VERSION 5.7 ;
  NOWIREEXTENSIONATPIN ON ;
  DIVIDERCHAR "/" ;
  BUSBITCHARS "[]" ;
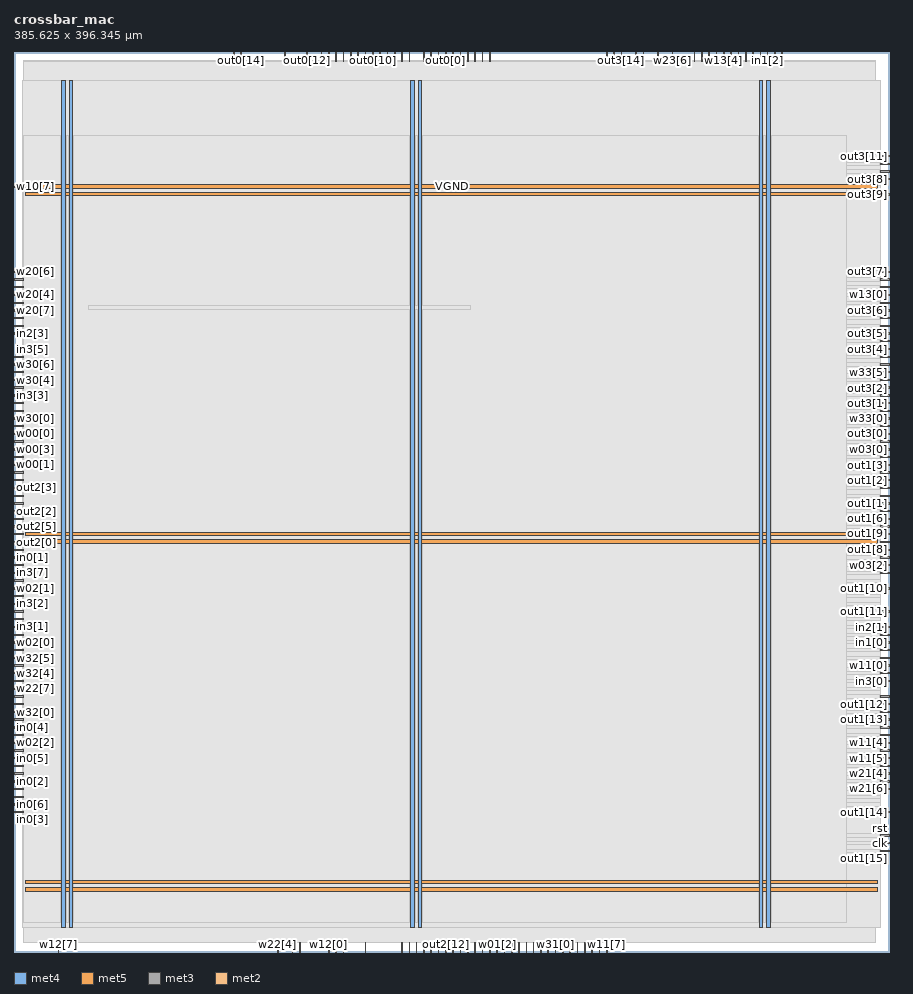
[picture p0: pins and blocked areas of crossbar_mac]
MACRO crossbar_mac
  CLASS BLOCK ;
  FOREIGN crossbar_mac ;
  ORIGIN 0.000 0.000 ;
  SIZE 385.625 BY 396.345 ;
  PIN VGND
    DIRECTION INOUT ;
    USE GROUND ;
    PORT
      LAYER met4 ;
        RECT 24.340 10.640 25.940 383.760 ;
    END
    PORT
      LAYER met4 ;
        RECT 177.940 10.640 179.540 383.760 ;
    END
    PORT
      LAYER met4 ;
        RECT 331.540 10.640 333.140 383.760 ;
    END
    PORT
      LAYER met5 ;
        RECT 5.280 30.030 380.200 31.630 ;
    END
    PORT
      LAYER met5 ;
        RECT 5.280 183.210 380.200 184.810 ;
    END
    PORT
      LAYER met5 ;
        RECT 5.280 336.390 380.200 337.990 ;
    END
  END VGND
  PIN VPWR
    DIRECTION INOUT ;
    USE POWER ;
    PORT
      LAYER met4 ;
        RECT 21.040 10.640 22.640 383.760 ;
    END
    PORT
      LAYER met4 ;
        RECT 174.640 10.640 176.240 383.760 ;
    END
    PORT
      LAYER met4 ;
        RECT 328.240 10.640 329.840 383.760 ;
    END
    PORT
      LAYER met5 ;
        RECT 5.280 26.730 380.200 28.330 ;
    END
    PORT
      LAYER met5 ;
        RECT 5.280 179.910 380.200 181.510 ;
    END
    PORT
      LAYER met5 ;
        RECT 5.280 333.090 380.200 334.690 ;
    END
  END VPWR
  PIN clk
    DIRECTION INPUT ;
    USE SIGNAL ;
    ANTENNAGATEAREA 0.852000 ;
    PORT
      LAYER met3 ;
        RECT 381.625 47.640 385.625 48.240 ;
    END
  END clk
  PIN in0[0]
    DIRECTION INPUT ;
    USE SIGNAL ;
    ANTENNAGATEAREA 0.213000 ;
    PORT
      LAYER met3 ;
        RECT 0.000 122.440 4.000 123.040 ;
    END
  END in0[0]
  PIN in0[1]
    DIRECTION INPUT ;
    USE SIGNAL ;
    ANTENNAGATEAREA 0.196500 ;
    PORT
      LAYER met3 ;
        RECT 0.000 173.440 4.000 174.040 ;
    END
  END in0[1]
  PIN in0[2]
    DIRECTION INPUT ;
    USE SIGNAL ;
    ANTENNAGATEAREA 0.495000 ;
    PORT
      LAYER met3 ;
        RECT 0.000 74.840 4.000 75.440 ;
    END
  END in0[2]
  PIN in0[3]
    DIRECTION INPUT ;
    USE SIGNAL ;
    ANTENNAGATEAREA 0.990000 ;
    PORT
      LAYER met3 ;
        RECT 0.000 61.240 4.000 61.840 ;
    END
  END in0[3]
  PIN in0[4]
    DIRECTION INPUT ;
    USE SIGNAL ;
    ANTENNAGATEAREA 0.990000 ;
    PORT
      LAYER met3 ;
        RECT 0.000 98.640 4.000 99.240 ;
    END
  END in0[4]
  PIN in0[5]
    DIRECTION INPUT ;
    USE SIGNAL ;
    ANTENNAGATEAREA 0.196500 ;
    PORT
      LAYER met3 ;
        RECT 0.000 85.040 4.000 85.640 ;
    END
  END in0[5]
  PIN in0[6]
    DIRECTION INPUT ;
    USE SIGNAL ;
    ANTENNAGATEAREA 0.159000 ;
    PORT
      LAYER met3 ;
        RECT 0.000 64.640 4.000 65.240 ;
    END
  END in0[6]
  PIN in0[7]
    DIRECTION INPUT ;
    USE SIGNAL ;
    ANTENNAGATEAREA 0.247500 ;
    PORT
      LAYER met3 ;
        RECT 0.000 88.440 4.000 89.040 ;
    END
  END in0[7]
  PIN in1[0]
    DIRECTION INPUT ;
    USE SIGNAL ;
    ANTENNAGATEAREA 0.213000 ;
    PORT
      LAYER met3 ;
        RECT 381.625 136.040 385.625 136.640 ;
    END
  END in1[0]
  PIN in1[1]
    DIRECTION INPUT ;
    USE SIGNAL ;
    ANTENNAGATEAREA 0.213000 ;
    PORT
      LAYER met2 ;
        RECT 338.190 392.345 338.470 396.345 ;
    END
  END in1[1]
  PIN in1[2]
    DIRECTION INPUT ;
    USE SIGNAL ;
    ANTENNAGATEAREA 0.196500 ;
    PORT
      LAYER met2 ;
        RECT 331.750 392.345 332.030 396.345 ;
    END
  END in1[2]
  PIN in1[3]
    DIRECTION INPUT ;
    USE SIGNAL ;
    ANTENNAGATEAREA 0.196500 ;
    PORT
      LAYER met2 ;
        RECT 334.970 392.345 335.250 396.345 ;
    END
  END in1[3]
  PIN in1[4]
    DIRECTION INPUT ;
    USE SIGNAL ;
    ANTENNAGATEAREA 0.196500 ;
    PORT
      LAYER met2 ;
        RECT 328.530 392.345 328.810 396.345 ;
    END
  END in1[4]
  PIN in1[5]
    DIRECTION INPUT ;
    USE SIGNAL ;
    ANTENNAGATEAREA 0.213000 ;
    PORT
      LAYER met2 ;
        RECT 325.310 392.345 325.590 396.345 ;
    END
  END in1[5]
  PIN in1[6]
    DIRECTION INPUT ;
    USE SIGNAL ;
    ANTENNAGATEAREA 0.213000 ;
    PORT
      LAYER met2 ;
        RECT 322.090 392.345 322.370 396.345 ;
    END
  END in1[6]
  PIN in1[7]
    DIRECTION INPUT ;
    USE SIGNAL ;
    ANTENNAGATEAREA 0.196500 ;
    PORT
      LAYER met2 ;
        RECT 318.870 392.345 319.150 396.345 ;
    END
  END in1[7]
  PIN in2[0]
    DIRECTION INPUT ;
    USE SIGNAL ;
    ANTENNAGATEAREA 0.213000 ;
    PORT
      LAYER met3 ;
        RECT 381.625 122.440 385.625 123.040 ;
    END
  END in2[0]
  PIN in2[1]
    DIRECTION INPUT ;
    USE SIGNAL ;
    ANTENNAGATEAREA 0.213000 ;
    PORT
      LAYER met3 ;
        RECT 381.625 139.440 385.625 140.040 ;
    END
  END in2[1]
  PIN in2[2]
    DIRECTION INPUT ;
    USE SIGNAL ;
    ANTENNAGATEAREA 0.196500 ;
    PORT
      LAYER met3 ;
        RECT 381.625 112.240 385.625 112.840 ;
    END
  END in2[2]
  PIN in2[3]
    DIRECTION INPUT ;
    USE SIGNAL ;
    ANTENNAGATEAREA 0.196500 ;
    PORT
      LAYER met3 ;
        RECT 0.000 272.040 4.000 272.640 ;
    END
  END in2[3]
  PIN in2[4]
    DIRECTION INPUT ;
    USE SIGNAL ;
    ANTENNAGATEAREA 0.213000 ;
    PORT
      LAYER met3 ;
        RECT 0.000 292.440 4.000 293.040 ;
    END
  END in2[4]
  PIN in2[5]
    DIRECTION INPUT ;
    USE SIGNAL ;
    ANTENNAGATEAREA 0.213000 ;
    PORT
      LAYER met3 ;
        RECT 0.000 278.840 4.000 279.440 ;
    END
  END in2[5]
  PIN in2[6]
    DIRECTION INPUT ;
    USE SIGNAL ;
    ANTENNAGATEAREA 0.159000 ;
    PORT
      LAYER met3 ;
        RECT 0.000 275.440 4.000 276.040 ;
    END
  END in2[6]
  PIN in2[7]
    DIRECTION INPUT ;
    USE SIGNAL ;
    ANTENNAGATEAREA 0.196500 ;
    PORT
      LAYER met3 ;
        RECT 0.000 285.640 4.000 286.240 ;
    END
  END in2[7]
  PIN in3[0]
    DIRECTION INPUT ;
    USE SIGNAL ;
    ANTENNAGATEAREA 0.159000 ;
    PORT
      LAYER met3 ;
        RECT 381.625 119.040 385.625 119.640 ;
    END
  END in3[0]
  PIN in3[1]
    DIRECTION INPUT ;
    USE SIGNAL ;
    ANTENNAGATEAREA 0.213000 ;
    PORT
      LAYER met3 ;
        RECT 0.000 142.840 4.000 143.440 ;
    END
  END in3[1]
  PIN in3[2]
    DIRECTION INPUT ;
    USE SIGNAL ;
    ANTENNAGATEAREA 0.159000 ;
    PORT
      LAYER met3 ;
        RECT 0.000 153.040 4.000 153.640 ;
    END
  END in3[2]
  PIN in3[3]
    DIRECTION INPUT ;
    USE SIGNAL ;
    ANTENNAGATEAREA 0.213000 ;
    PORT
      LAYER met3 ;
        RECT 0.000 244.840 4.000 245.440 ;
    END
  END in3[3]
  PIN in3[4]
    DIRECTION INPUT ;
    USE SIGNAL ;
    ANTENNAGATEAREA 0.196500 ;
    PORT
      LAYER met3 ;
        RECT 0.000 112.240 4.000 112.840 ;
    END
  END in3[4]
  PIN in3[5]
    DIRECTION INPUT ;
    USE SIGNAL ;
    ANTENNAGATEAREA 0.196500 ;
    PORT
      LAYER met3 ;
        RECT 0.000 261.840 4.000 262.440 ;
    END
  END in3[5]
  PIN in3[6]
    DIRECTION INPUT ;
    USE SIGNAL ;
    ANTENNAGATEAREA 0.213000 ;
    PORT
      LAYER met3 ;
        RECT 0.000 105.440 4.000 106.040 ;
    END
  END in3[6]
  PIN in3[7]
    DIRECTION INPUT ;
    USE SIGNAL ;
    ANTENNAGATEAREA 0.213000 ;
    PORT
      LAYER met3 ;
        RECT 0.000 170.040 4.000 170.640 ;
    END
  END in3[7]
  PIN out0[0]
    DIRECTION OUTPUT ;
    USE SIGNAL ;
    ANTENNADIFFAREA 0.445500 ;
    PORT
      LAYER met2 ;
        RECT 190.070 392.345 190.350 396.345 ;
    END
  END out0[0]
  PIN out0[10]
    DIRECTION OUTPUT ;
    USE SIGNAL ;
    ANTENNADIFFAREA 0.445500 ;
    PORT
      LAYER met2 ;
        RECT 157.870 392.345 158.150 396.345 ;
    END
  END out0[10]
  PIN out0[11]
    DIRECTION OUTPUT ;
    USE SIGNAL ;
    ANTENNADIFFAREA 0.445500 ;
    PORT
      LAYER met2 ;
        RECT 151.430 392.345 151.710 396.345 ;
    END
  END out0[11]
  PIN out0[12]
    DIRECTION OUTPUT ;
    USE SIGNAL ;
    ANTENNADIFFAREA 0.445500 ;
    PORT
      LAYER met2 ;
        RECT 128.890 392.345 129.170 396.345 ;
    END
  END out0[12]
  PIN out0[13]
    DIRECTION OUTPUT ;
    USE SIGNAL ;
    ANTENNADIFFAREA 0.445500 ;
    PORT
      LAYER met2 ;
        RECT 119.230 392.345 119.510 396.345 ;
    END
  END out0[13]
  PIN out0[14]
    DIRECTION OUTPUT ;
    USE SIGNAL ;
    ANTENNADIFFAREA 0.445500 ;
    PORT
      LAYER met2 ;
        RECT 99.910 392.345 100.190 396.345 ;
    END
  END out0[14]
  PIN out0[15]
    DIRECTION OUTPUT ;
    USE SIGNAL ;
    ANTENNADIFFAREA 0.445500 ;
    PORT
      LAYER met2 ;
        RECT 96.690 392.345 96.970 396.345 ;
    END
  END out0[15]
  PIN out0[1]
    DIRECTION OUTPUT ;
    USE SIGNAL ;
    ANTENNADIFFAREA 0.445500 ;
    PORT
      LAYER met2 ;
        RECT 196.510 392.345 196.790 396.345 ;
    END
  END out0[1]
  PIN out0[2]
    DIRECTION OUTPUT ;
    USE SIGNAL ;
    ANTENNADIFFAREA 0.445500 ;
    PORT
      LAYER met2 ;
        RECT 209.390 392.345 209.670 396.345 ;
    END
  END out0[2]
  PIN out0[3]
    DIRECTION OUTPUT ;
    USE SIGNAL ;
    ANTENNADIFFAREA 0.445500 ;
    PORT
      LAYER met2 ;
        RECT 206.170 392.345 206.450 396.345 ;
    END
  END out0[3]
  PIN out0[4]
    DIRECTION OUTPUT ;
    USE SIGNAL ;
    ANTENNADIFFAREA 0.445500 ;
    PORT
      LAYER met2 ;
        RECT 199.730 392.345 200.010 396.345 ;
    END
  END out0[4]
  PIN out0[5]
    DIRECTION OUTPUT ;
    USE SIGNAL ;
    ANTENNADIFFAREA 0.445500 ;
    PORT
      LAYER met2 ;
        RECT 202.950 392.345 203.230 396.345 ;
    END
  END out0[5]
  PIN out0[6]
    DIRECTION OUTPUT ;
    USE SIGNAL ;
    ANTENNADIFFAREA 0.445500 ;
    PORT
      LAYER met2 ;
        RECT 193.290 392.345 193.570 396.345 ;
    END
  END out0[6]
  PIN out0[7]
    DIRECTION OUTPUT ;
    USE SIGNAL ;
    ANTENNADIFFAREA 0.445500 ;
    PORT
      LAYER met2 ;
        RECT 186.850 392.345 187.130 396.345 ;
    END
  END out0[7]
  PIN out0[8]
    DIRECTION OUTPUT ;
    USE SIGNAL ;
    ANTENNADIFFAREA 0.445500 ;
    PORT
      LAYER met2 ;
        RECT 183.630 392.345 183.910 396.345 ;
    END
  END out0[8]
  PIN out0[9]
    DIRECTION OUTPUT ;
    USE SIGNAL ;
    ANTENNADIFFAREA 0.445500 ;
    PORT
      LAYER met2 ;
        RECT 180.410 392.345 180.690 396.345 ;
    END
  END out0[9]
  PIN out1[0]
    DIRECTION OUTPUT ;
    USE SIGNAL ;
    ANTENNADIFFAREA 0.445500 ;
    PORT
      LAYER met3 ;
        RECT 381.625 166.640 385.625 167.240 ;
    END
  END out1[0]
  PIN out1[10]
    DIRECTION OUTPUT ;
    USE SIGNAL ;
    ANTENNADIFFAREA 0.445500 ;
    PORT
      LAYER met3 ;
        RECT 381.625 159.840 385.625 160.440 ;
    END
  END out1[10]
  PIN out1[11]
    DIRECTION OUTPUT ;
    USE SIGNAL ;
    ANTENNADIFFAREA 0.445500 ;
    PORT
      LAYER met3 ;
        RECT 381.625 149.640 385.625 150.240 ;
    END
  END out1[11]
  PIN out1[12]
    DIRECTION OUTPUT ;
    USE SIGNAL ;
    ANTENNADIFFAREA 0.445500 ;
    PORT
      LAYER met3 ;
        RECT 381.625 108.840 385.625 109.440 ;
    END
  END out1[12]
  PIN out1[13]
    DIRECTION OUTPUT ;
    USE SIGNAL ;
    ANTENNADIFFAREA 0.445500 ;
    PORT
      LAYER met3 ;
        RECT 381.625 102.040 385.625 102.640 ;
    END
  END out1[13]
  PIN out1[14]
    DIRECTION OUTPUT ;
    USE SIGNAL ;
    ANTENNADIFFAREA 0.445500 ;
    PORT
      LAYER met3 ;
        RECT 381.625 61.240 385.625 61.840 ;
    END
  END out1[14]
  PIN out1[15]
    DIRECTION OUTPUT ;
    USE SIGNAL ;
    ANTENNADIFFAREA 0.445500 ;
    PORT
      LAYER met3 ;
        RECT 381.625 44.240 385.625 44.840 ;
    END
  END out1[15]
  PIN out1[1]
    DIRECTION OUTPUT ;
    USE SIGNAL ;
    ANTENNADIFFAREA 0.445500 ;
    PORT
      LAYER met3 ;
        RECT 381.625 197.240 385.625 197.840 ;
    END
  END out1[1]
  PIN out1[2]
    DIRECTION OUTPUT ;
    USE SIGNAL ;
    ANTENNADIFFAREA 0.445500 ;
    PORT
      LAYER met3 ;
        RECT 381.625 207.440 385.625 208.040 ;
    END
  END out1[2]
  PIN out1[3]
    DIRECTION OUTPUT ;
    USE SIGNAL ;
    ANTENNADIFFAREA 0.445500 ;
    PORT
      LAYER met3 ;
        RECT 381.625 210.840 385.625 211.440 ;
    END
  END out1[3]
  PIN out1[4]
    DIRECTION OUTPUT ;
    USE SIGNAL ;
    ANTENNADIFFAREA 0.445500 ;
    PORT
      LAYER met3 ;
        RECT 381.625 204.040 385.625 204.640 ;
    END
  END out1[4]
  PIN out1[5]
    DIRECTION OUTPUT ;
    USE SIGNAL ;
    ANTENNADIFFAREA 0.445500 ;
    PORT
      LAYER met3 ;
        RECT 381.625 200.640 385.625 201.240 ;
    END
  END out1[5]
  PIN out1[6]
    DIRECTION OUTPUT ;
    USE SIGNAL ;
    ANTENNADIFFAREA 0.445500 ;
    PORT
      LAYER met3 ;
        RECT 381.625 193.840 385.625 194.440 ;
    END
  END out1[6]
  PIN out1[7]
    DIRECTION OUTPUT ;
    USE SIGNAL ;
    ANTENNADIFFAREA 0.445500 ;
    PORT
      LAYER met3 ;
        RECT 381.625 190.440 385.625 191.040 ;
    END
  END out1[7]
  PIN out1[8]
    DIRECTION OUTPUT ;
    USE SIGNAL ;
    ANTENNADIFFAREA 0.445500 ;
    PORT
      LAYER met3 ;
        RECT 381.625 176.840 385.625 177.440 ;
    END
  END out1[8]
  PIN out1[9]
    DIRECTION OUTPUT ;
    USE SIGNAL ;
    ANTENNADIFFAREA 0.445500 ;
    PORT
      LAYER met3 ;
        RECT 381.625 187.040 385.625 187.640 ;
    END
  END out1[9]
  PIN out2[0]
    DIRECTION OUTPUT ;
    USE SIGNAL ;
    ANTENNADIFFAREA 0.445500 ;
    PORT
      LAYER met3 ;
        RECT 0.000 176.840 4.000 177.440 ;
    END
  END out2[0]
  PIN out2[10]
    DIRECTION OUTPUT ;
    USE SIGNAL ;
    ANTENNADIFFAREA 0.445500 ;
    PORT
      LAYER met2 ;
        RECT 206.170 0.000 206.450 4.000 ;
    END
  END out2[10]
  PIN out2[11]
    DIRECTION OUTPUT ;
    USE SIGNAL ;
    ANTENNADIFFAREA 0.445500 ;
    PORT
      LAYER met2 ;
        RECT 222.270 0.000 222.550 4.000 ;
    END
  END out2[11]
  PIN out2[12]
    DIRECTION OUTPUT ;
    USE SIGNAL ;
    ANTENNADIFFAREA 0.445500 ;
    PORT
      LAYER met2 ;
        RECT 190.070 0.000 190.350 4.000 ;
    END
  END out2[12]
  PIN out2[13]
    DIRECTION OUTPUT ;
    USE SIGNAL ;
    ANTENNADIFFAREA 0.445500 ;
    PORT
      LAYER met2 ;
        RECT 186.850 0.000 187.130 4.000 ;
    END
  END out2[13]
  PIN out2[14]
    DIRECTION OUTPUT ;
    USE SIGNAL ;
    ANTENNADIFFAREA 0.445500 ;
    PORT
      LAYER met2 ;
        RECT 180.410 0.000 180.690 4.000 ;
    END
  END out2[14]
  PIN out2[15]
    DIRECTION OUTPUT ;
    USE SIGNAL ;
    ANTENNADIFFAREA 0.445500 ;
    PORT
      LAYER met2 ;
        RECT 177.190 0.000 177.470 4.000 ;
    END
  END out2[15]
  PIN out2[1]
    DIRECTION OUTPUT ;
    USE SIGNAL ;
    ANTENNADIFFAREA 0.445500 ;
    PORT
      LAYER met3 ;
        RECT 0.000 180.240 4.000 180.840 ;
    END
  END out2[1]
  PIN out2[2]
    DIRECTION OUTPUT ;
    USE SIGNAL ;
    ANTENNADIFFAREA 0.445500 ;
    PORT
      LAYER met3 ;
        RECT 0.000 193.840 4.000 194.440 ;
    END
  END out2[2]
  PIN out2[3]
    DIRECTION OUTPUT ;
    USE SIGNAL ;
    ANTENNADIFFAREA 0.445500 ;
    PORT
      LAYER met3 ;
        RECT 0.000 204.040 4.000 204.640 ;
    END
  END out2[3]
  PIN out2[4]
    DIRECTION OUTPUT ;
    USE SIGNAL ;
    ANTENNADIFFAREA 0.445500 ;
    PORT
      LAYER met3 ;
        RECT 0.000 200.640 4.000 201.240 ;
    END
  END out2[4]
  PIN out2[5]
    DIRECTION OUTPUT ;
    USE SIGNAL ;
    ANTENNADIFFAREA 0.445500 ;
    PORT
      LAYER met3 ;
        RECT 0.000 190.440 4.000 191.040 ;
    END
  END out2[5]
  PIN out2[6]
    DIRECTION OUTPUT ;
    USE SIGNAL ;
    ANTENNADIFFAREA 0.445500 ;
    PORT
      LAYER met3 ;
        RECT 0.000 197.240 4.000 197.840 ;
    END
  END out2[6]
  PIN out2[7]
    DIRECTION OUTPUT ;
    USE SIGNAL ;
    ANTENNADIFFAREA 0.445500 ;
    PORT
      LAYER met3 ;
        RECT 0.000 183.640 4.000 184.240 ;
    END
  END out2[7]
  PIN out2[8]
    DIRECTION OUTPUT ;
    USE SIGNAL ;
    ANTENNADIFFAREA 0.445500 ;
    PORT
      LAYER met2 ;
        RECT 199.730 0.000 200.010 4.000 ;
    END
  END out2[8]
  PIN out2[9]
    DIRECTION OUTPUT ;
    USE SIGNAL ;
    ANTENNADIFFAREA 0.445500 ;
    PORT
      LAYER met2 ;
        RECT 202.950 0.000 203.230 4.000 ;
    END
  END out2[9]
  PIN out3[0]
    DIRECTION OUTPUT ;
    USE SIGNAL ;
    ANTENNADIFFAREA 0.445500 ;
    PORT
      LAYER met3 ;
        RECT 381.625 227.840 385.625 228.440 ;
    END
  END out3[0]
  PIN out3[10]
    DIRECTION OUTPUT ;
    USE SIGNAL ;
    ANTENNADIFFAREA 0.445500 ;
    PORT
      LAYER met3 ;
        RECT 381.625 343.440 385.625 344.040 ;
    END
  END out3[10]
  PIN out3[11]
    DIRECTION OUTPUT ;
    USE SIGNAL ;
    ANTENNADIFFAREA 0.445500 ;
    PORT
      LAYER met3 ;
        RECT 381.625 350.240 385.625 350.840 ;
    END
  END out3[11]
  PIN out3[12]
    DIRECTION OUTPUT ;
    USE SIGNAL ;
    ANTENNADIFFAREA 0.445500 ;
    PORT
      LAYER met3 ;
        RECT 381.625 346.840 385.625 347.440 ;
    END
  END out3[12]
  PIN out3[13]
    DIRECTION OUTPUT ;
    USE SIGNAL ;
    ANTENNADIFFAREA 0.445500 ;
    PORT
      LAYER met2 ;
        RECT 283.450 392.345 283.730 396.345 ;
    END
  END out3[13]
  PIN out3[14]
    DIRECTION OUTPUT ;
    USE SIGNAL ;
    ANTENNADIFFAREA 0.445500 ;
    PORT
      LAYER met2 ;
        RECT 267.350 392.345 267.630 396.345 ;
    END
  END out3[14]
  PIN out3[15]
    DIRECTION OUTPUT ;
    USE SIGNAL ;
    ANTENNADIFFAREA 0.445500 ;
    PORT
      LAYER met2 ;
        RECT 264.130 392.345 264.410 396.345 ;
    END
  END out3[15]
  PIN out3[1]
    DIRECTION OUTPUT ;
    USE SIGNAL ;
    ANTENNADIFFAREA 0.445500 ;
    PORT
      LAYER met3 ;
        RECT 381.625 241.440 385.625 242.040 ;
    END
  END out3[1]
  PIN out3[2]
    DIRECTION OUTPUT ;
    USE SIGNAL ;
    ANTENNADIFFAREA 0.445500 ;
    PORT
      LAYER met3 ;
        RECT 381.625 244.840 385.625 245.440 ;
    END
  END out3[2]
  PIN out3[3]
    DIRECTION OUTPUT ;
    USE SIGNAL ;
    ANTENNADIFFAREA 0.445500 ;
    PORT
      LAYER met3 ;
        RECT 381.625 251.640 385.625 252.240 ;
    END
  END out3[3]
  PIN out3[4]
    DIRECTION OUTPUT ;
    USE SIGNAL ;
    ANTENNADIFFAREA 0.445500 ;
    PORT
      LAYER met3 ;
        RECT 381.625 265.240 385.625 265.840 ;
    END
  END out3[4]
  PIN out3[5]
    DIRECTION OUTPUT ;
    USE SIGNAL ;
    ANTENNADIFFAREA 0.445500 ;
    PORT
      LAYER met3 ;
        RECT 381.625 272.040 385.625 272.640 ;
    END
  END out3[5]
  PIN out3[6]
    DIRECTION OUTPUT ;
    USE SIGNAL ;
    ANTENNADIFFAREA 0.445500 ;
    PORT
      LAYER met3 ;
        RECT 381.625 282.240 385.625 282.840 ;
    END
  END out3[6]
  PIN out3[7]
    DIRECTION OUTPUT ;
    USE SIGNAL ;
    ANTENNADIFFAREA 0.445500 ;
    PORT
      LAYER met3 ;
        RECT 381.625 299.240 385.625 299.840 ;
    END
  END out3[7]
  PIN out3[8]
    DIRECTION OUTPUT ;
    USE SIGNAL ;
    ANTENNADIFFAREA 0.445500 ;
    PORT
      LAYER met3 ;
        RECT 381.625 340.040 385.625 340.640 ;
    END
  END out3[8]
  PIN out3[9]
    DIRECTION OUTPUT ;
    USE SIGNAL ;
    ANTENNADIFFAREA 0.445500 ;
    PORT
      LAYER met3 ;
        RECT 381.625 333.240 385.625 333.840 ;
    END
  END out3[9]
  PIN rst
    DIRECTION INPUT ;
    USE SIGNAL ;
    ANTENNAGATEAREA 0.247500 ;
    PORT
      LAYER met3 ;
        RECT 381.625 51.040 385.625 51.640 ;
    END
  END rst
  PIN w00[0]
    DIRECTION INPUT ;
    USE SIGNAL ;
    ANTENNAGATEAREA 0.159000 ;
    PORT
      LAYER met3 ;
        RECT 0.000 227.840 4.000 228.440 ;
    END
  END w00[0]
  PIN w00[1]
    DIRECTION INPUT ;
    USE SIGNAL ;
    ANTENNAGATEAREA 0.196500 ;
    PORT
      LAYER met3 ;
        RECT 0.000 214.240 4.000 214.840 ;
    END
  END w00[1]
  PIN w00[2]
    DIRECTION INPUT ;
    USE SIGNAL ;
    ANTENNAGATEAREA 0.213000 ;
    PORT
      LAYER met3 ;
        RECT 0.000 210.840 4.000 211.440 ;
    END
  END w00[2]
  PIN w00[3]
    DIRECTION INPUT ;
    USE SIGNAL ;
    ANTENNAGATEAREA 0.196500 ;
    PORT
      LAYER met3 ;
        RECT 0.000 221.040 4.000 221.640 ;
    END
  END w00[3]
  PIN w00[4]
    DIRECTION INPUT ;
    USE SIGNAL ;
    ANTENNAGATEAREA 0.196500 ;
    PORT
      LAYER met3 ;
        RECT 0.000 217.640 4.000 218.240 ;
    END
  END w00[4]
  PIN w00[5]
    DIRECTION INPUT ;
    USE SIGNAL ;
    ANTENNAGATEAREA 0.196500 ;
    PORT
      LAYER met3 ;
        RECT 0.000 207.440 4.000 208.040 ;
    END
  END w00[5]
  PIN w00[6]
    DIRECTION INPUT ;
    USE SIGNAL ;
    ANTENNAGATEAREA 0.213000 ;
    PORT
      LAYER met3 ;
        RECT 0.000 187.040 4.000 187.640 ;
    END
  END w00[6]
  PIN w00[7]
    DIRECTION INPUT ;
    USE SIGNAL ;
    ANTENNAGATEAREA 0.126000 ;
    PORT
      LAYER met3 ;
        RECT 0.000 224.440 4.000 225.040 ;
    END
  END w00[7]
  PIN w01[0]
    DIRECTION INPUT ;
    USE SIGNAL ;
    ANTENNAGATEAREA 0.213000 ;
    PORT
      LAYER met2 ;
        RECT 228.710 0.000 228.990 4.000 ;
    END
  END w01[0]
  PIN w01[1]
    DIRECTION INPUT ;
    USE SIGNAL ;
    ANTENNAGATEAREA 0.196500 ;
    PORT
      LAYER met2 ;
        RECT 225.490 0.000 225.770 4.000 ;
    END
  END w01[1]
  PIN w01[2]
    DIRECTION INPUT ;
    USE SIGNAL ;
    ANTENNAGATEAREA 0.213000 ;
    PORT
      LAYER met2 ;
        RECT 212.610 0.000 212.890 4.000 ;
    END
  END w01[2]
  PIN w01[3]
    DIRECTION INPUT ;
    USE SIGNAL ;
    ANTENNAGATEAREA 0.196500 ;
    PORT
      LAYER met2 ;
        RECT 219.050 0.000 219.330 4.000 ;
    END
  END w01[3]
  PIN w01[4]
    DIRECTION INPUT ;
    USE SIGNAL ;
    ANTENNAGATEAREA 0.196500 ;
    PORT
      LAYER met2 ;
        RECT 209.390 0.000 209.670 4.000 ;
    END
  END w01[4]
  PIN w01[5]
    DIRECTION INPUT ;
    USE SIGNAL ;
    ANTENNAGATEAREA 0.196500 ;
    PORT
      LAYER met2 ;
        RECT 196.510 0.000 196.790 4.000 ;
    END
  END w01[5]
  PIN w01[6]
    DIRECTION INPUT ;
    USE SIGNAL ;
    ANTENNAGATEAREA 0.213000 ;
    PORT
      LAYER met2 ;
        RECT 215.830 0.000 216.110 4.000 ;
    END
  END w01[6]
  PIN w01[7]
    DIRECTION INPUT ;
    USE SIGNAL ;
    ANTENNAGATEAREA 0.196500 ;
    PORT
      LAYER met2 ;
        RECT 193.290 0.000 193.570 4.000 ;
    END
  END w01[7]
  PIN w02[0]
    DIRECTION INPUT ;
    USE SIGNAL ;
    ANTENNAGATEAREA 0.196500 ;
    PORT
      LAYER met3 ;
        RECT 0.000 139.440 4.000 140.040 ;
    END
  END w02[0]
  PIN w02[1]
    DIRECTION INPUT ;
    USE SIGNAL ;
    ANTENNAGATEAREA 0.196500 ;
    PORT
      LAYER met3 ;
        RECT 0.000 159.840 4.000 160.440 ;
    END
  END w02[1]
  PIN w02[2]
    DIRECTION INPUT ;
    USE SIGNAL ;
    ANTENNAGATEAREA 0.159000 ;
    PORT
      LAYER met3 ;
        RECT 0.000 91.840 4.000 92.440 ;
    END
  END w02[2]
  PIN w02[3]
    DIRECTION INPUT ;
    USE SIGNAL ;
    ANTENNAGATEAREA 0.196500 ;
    PORT
      LAYER met3 ;
        RECT 0.000 68.040 4.000 68.640 ;
    END
  END w02[3]
  PIN w02[4]
    DIRECTION INPUT ;
    USE SIGNAL ;
    ANTENNAGATEAREA 0.196500 ;
    PORT
      LAYER met3 ;
        RECT 0.000 132.640 4.000 133.240 ;
    END
  END w02[4]
  PIN w02[5]
    DIRECTION INPUT ;
    USE SIGNAL ;
    ANTENNAGATEAREA 0.196500 ;
    PORT
      LAYER met3 ;
        RECT 0.000 78.240 4.000 78.840 ;
    END
  END w02[5]
  PIN w02[6]
    DIRECTION INPUT ;
    USE SIGNAL ;
    ANTENNAGATEAREA 0.126000 ;
    PORT
      LAYER met3 ;
        RECT 0.000 81.640 4.000 82.240 ;
    END
  END w02[6]
  PIN w02[7]
    DIRECTION INPUT ;
    USE SIGNAL ;
    ANTENNAGATEAREA 0.196500 ;
    PORT
      LAYER met3 ;
        RECT 0.000 95.240 4.000 95.840 ;
    END
  END w02[7]
  PIN w03[0]
    DIRECTION INPUT ;
    USE SIGNAL ;
    ANTENNAGATEAREA 0.196500 ;
    PORT
      LAYER met3 ;
        RECT 381.625 221.040 385.625 221.640 ;
    END
  END w03[0]
  PIN w03[1]
    DIRECTION INPUT ;
    USE SIGNAL ;
    ANTENNAGATEAREA 0.196500 ;
    PORT
      LAYER met3 ;
        RECT 381.625 214.240 385.625 214.840 ;
    END
  END w03[1]
  PIN w03[2]
    DIRECTION INPUT ;
    USE SIGNAL ;
    ANTENNAGATEAREA 0.213000 ;
    PORT
      LAYER met3 ;
        RECT 381.625 170.040 385.625 170.640 ;
    END
  END w03[2]
  PIN w03[3]
    DIRECTION INPUT ;
    USE SIGNAL ;
    ANTENNAGATEAREA 0.196500 ;
    PORT
      LAYER met3 ;
        RECT 381.625 217.640 385.625 218.240 ;
    END
  END w03[3]
  PIN w03[4]
    DIRECTION INPUT ;
    USE SIGNAL ;
    ANTENNAGATEAREA 0.196500 ;
    PORT
      LAYER met3 ;
        RECT 381.625 224.440 385.625 225.040 ;
    END
  END w03[4]
  PIN w03[5]
    DIRECTION INPUT ;
    USE SIGNAL ;
    ANTENNAGATEAREA 0.213000 ;
    PORT
      LAYER met3 ;
        RECT 381.625 173.440 385.625 174.040 ;
    END
  END w03[5]
  PIN w03[6]
    DIRECTION INPUT ;
    USE SIGNAL ;
    ANTENNAGATEAREA 0.213000 ;
    PORT
      LAYER met3 ;
        RECT 381.625 180.240 385.625 180.840 ;
    END
  END w03[6]
  PIN w03[7]
    DIRECTION INPUT ;
    USE SIGNAL ;
    ANTENNAGATEAREA 0.213000 ;
    PORT
      LAYER met3 ;
        RECT 381.625 183.640 385.625 184.240 ;
    END
  END w03[7]
  PIN w10[0]
    DIRECTION INPUT ;
    USE SIGNAL ;
    ANTENNAGATEAREA 0.196500 ;
    PORT
      LAYER met2 ;
        RECT 173.970 392.345 174.250 396.345 ;
    END
  END w10[0]
  PIN w10[1]
    DIRECTION INPUT ;
    USE SIGNAL ;
    ANTENNAGATEAREA 0.196500 ;
    PORT
      LAYER met2 ;
        RECT 170.750 392.345 171.030 396.345 ;
    END
  END w10[1]
  PIN w10[2]
    DIRECTION INPUT ;
    USE SIGNAL ;
    ANTENNAGATEAREA 0.196500 ;
    PORT
      LAYER met2 ;
        RECT 167.530 392.345 167.810 396.345 ;
    END
  END w10[2]
  PIN w10[3]
    DIRECTION INPUT ;
    USE SIGNAL ;
    ANTENNAGATEAREA 0.196500 ;
    PORT
      LAYER met2 ;
        RECT 164.310 392.345 164.590 396.345 ;
    END
  END w10[3]
  PIN w10[4]
    DIRECTION INPUT ;
    USE SIGNAL ;
    ANTENNAGATEAREA 0.196500 ;
    PORT
      LAYER met2 ;
        RECT 154.650 392.345 154.930 396.345 ;
    END
  END w10[4]
  PIN w10[5]
    DIRECTION INPUT ;
    USE SIGNAL ;
    ANTENNAGATEAREA 0.196500 ;
    PORT
      LAYER met2 ;
        RECT 148.210 392.345 148.490 396.345 ;
    END
  END w10[5]
  PIN w10[6]
    DIRECTION INPUT ;
    USE SIGNAL ;
    ANTENNAGATEAREA 0.196500 ;
    PORT
      LAYER met2 ;
        RECT 144.990 392.345 145.270 396.345 ;
    END
  END w10[6]
  PIN w10[7]
    DIRECTION INPUT ;
    USE SIGNAL ;
    ANTENNAGATEAREA 0.213000 ;
    PORT
      LAYER met3 ;
        RECT 0.000 336.640 4.000 337.240 ;
    END
  END w10[7]
  PIN w11[0]
    DIRECTION INPUT ;
    USE SIGNAL ;
    ANTENNAGATEAREA 0.196500 ;
    PORT
      LAYER met3 ;
        RECT 381.625 125.840 385.625 126.440 ;
    END
  END w11[0]
  PIN w11[1]
    DIRECTION INPUT ;
    USE SIGNAL ;
    ANTENNAGATEAREA 0.196500 ;
    PORT
      LAYER met3 ;
        RECT 381.625 129.240 385.625 129.840 ;
    END
  END w11[1]
  PIN w11[2]
    DIRECTION INPUT ;
    USE SIGNAL ;
    ANTENNAGATEAREA 0.126000 ;
    PORT
      LAYER met3 ;
        RECT 381.625 132.640 385.625 133.240 ;
    END
  END w11[2]
  PIN w11[3]
    DIRECTION INPUT ;
    USE SIGNAL ;
    ANTENNAGATEAREA 0.196500 ;
    PORT
      LAYER met3 ;
        RECT 381.625 88.440 385.625 89.040 ;
    END
  END w11[3]
  PIN w11[4]
    DIRECTION INPUT ;
    USE SIGNAL ;
    ANTENNAGATEAREA 0.196500 ;
    PORT
      LAYER met3 ;
        RECT 381.625 91.840 385.625 92.440 ;
    END
  END w11[4]
  PIN w11[5]
    DIRECTION INPUT ;
    USE SIGNAL ;
    ANTENNAGATEAREA 0.196500 ;
    PORT
      LAYER met3 ;
        RECT 381.625 85.040 385.625 85.640 ;
    END
  END w11[5]
  PIN w11[6]
    DIRECTION INPUT ;
    USE SIGNAL ;
    ANTENNAGATEAREA 0.196500 ;
    PORT
      LAYER met3 ;
        RECT 381.625 78.240 385.625 78.840 ;
    END
  END w11[6]
  PIN w11[7]
    DIRECTION INPUT ;
    USE SIGNAL ;
    ANTENNAGATEAREA 0.213000 ;
    PORT
      LAYER met2 ;
        RECT 260.910 0.000 261.190 4.000 ;
    END
  END w11[7]
  PIN w12[0]
    DIRECTION INPUT ;
    USE SIGNAL ;
    ANTENNAGATEAREA 0.196500 ;
    PORT
      LAYER met2 ;
        RECT 138.550 0.000 138.830 4.000 ;
    END
  END w12[0]
  PIN w12[1]
    DIRECTION INPUT ;
    USE SIGNAL ;
    ANTENNAGATEAREA 0.196500 ;
    PORT
      LAYER met2 ;
        RECT 141.770 0.000 142.050 4.000 ;
    END
  END w12[1]
  PIN w12[2]
    DIRECTION INPUT ;
    USE SIGNAL ;
    ANTENNAGATEAREA 0.159000 ;
    PORT
      LAYER met2 ;
        RECT 144.990 0.000 145.270 4.000 ;
    END
  END w12[2]
  PIN w12[3]
    DIRECTION INPUT ;
    USE SIGNAL ;
    ANTENNAGATEAREA 0.126000 ;
    PORT
      LAYER met2 ;
        RECT 170.750 0.000 171.030 4.000 ;
    END
  END w12[3]
  PIN w12[4]
    DIRECTION INPUT ;
    USE SIGNAL ;
    ANTENNAGATEAREA 0.126000 ;
    PORT
      LAYER met2 ;
        RECT 173.970 0.000 174.250 4.000 ;
    END
  END w12[4]
  PIN w12[5]
    DIRECTION INPUT ;
    USE SIGNAL ;
    ANTENNAGATEAREA 0.213000 ;
    PORT
      LAYER met2 ;
        RECT 183.630 0.000 183.910 4.000 ;
    END
  END w12[5]
  PIN w12[6]
    DIRECTION INPUT ;
    USE SIGNAL ;
    ANTENNAGATEAREA 0.196500 ;
    PORT
      LAYER met2 ;
        RECT 154.650 0.000 154.930 4.000 ;
    END
  END w12[6]
  PIN w12[7]
    DIRECTION INPUT ;
    USE SIGNAL ;
    ANTENNAGATEAREA 0.247500 ;
    PORT
      LAYER met2 ;
        RECT 19.410 0.000 19.690 4.000 ;
    END
  END w12[7]
  PIN w13[0]
    DIRECTION INPUT ;
    USE SIGNAL ;
    ANTENNAGATEAREA 0.196500 ;
    PORT
      LAYER met3 ;
        RECT 381.625 289.040 385.625 289.640 ;
    END
  END w13[0]
  PIN w13[1]
    DIRECTION INPUT ;
    USE SIGNAL ;
    ANTENNAGATEAREA 0.196500 ;
    PORT
      LAYER met3 ;
        RECT 381.625 292.440 385.625 293.040 ;
    END
  END w13[1]
  PIN w13[2]
    DIRECTION INPUT ;
    USE SIGNAL ;
    ANTENNAGATEAREA 0.196500 ;
    PORT
      LAYER met3 ;
        RECT 381.625 295.840 385.625 296.440 ;
    END
  END w13[2]
  PIN w13[3]
    DIRECTION INPUT ;
    USE SIGNAL ;
    ANTENNAGATEAREA 0.196500 ;
    PORT
      LAYER met2 ;
        RECT 315.650 392.345 315.930 396.345 ;
    END
  END w13[3]
  PIN w13[4]
    DIRECTION INPUT ;
    USE SIGNAL ;
    ANTENNAGATEAREA 0.196500 ;
    PORT
      LAYER met2 ;
        RECT 312.430 392.345 312.710 396.345 ;
    END
  END w13[4]
  PIN w13[5]
    DIRECTION INPUT ;
    USE SIGNAL ;
    ANTENNAGATEAREA 0.196500 ;
    PORT
      LAYER met2 ;
        RECT 309.210 392.345 309.490 396.345 ;
    END
  END w13[5]
  PIN w13[6]
    DIRECTION INPUT ;
    USE SIGNAL ;
    ANTENNAGATEAREA 0.196500 ;
    PORT
      LAYER met2 ;
        RECT 305.990 392.345 306.270 396.345 ;
    END
  END w13[6]
  PIN w13[7]
    DIRECTION INPUT ;
    USE SIGNAL ;
    ANTENNAGATEAREA 0.213000 ;
    PORT
      LAYER met2 ;
        RECT 277.010 392.345 277.290 396.345 ;
    END
  END w13[7]
  PIN w20[0]
    DIRECTION INPUT ;
    USE SIGNAL ;
    ANTENNAGATEAREA 0.213000 ;
    PORT
      LAYER met2 ;
        RECT 161.090 392.345 161.370 396.345 ;
    END
  END w20[0]
  PIN w20[1]
    DIRECTION INPUT ;
    USE SIGNAL ;
    ANTENNAGATEAREA 0.213000 ;
    PORT
      LAYER met2 ;
        RECT 141.770 392.345 142.050 396.345 ;
    END
  END w20[1]
  PIN w20[2]
    DIRECTION INPUT ;
    USE SIGNAL ;
    ANTENNAGATEAREA 0.196500 ;
    PORT
      LAYER met2 ;
        RECT 138.550 392.345 138.830 396.345 ;
    END
  END w20[2]
  PIN w20[3]
    DIRECTION INPUT ;
    USE SIGNAL ;
    ANTENNAGATEAREA 0.196500 ;
    PORT
      LAYER met2 ;
        RECT 135.330 392.345 135.610 396.345 ;
    END
  END w20[3]
  PIN w20[4]
    DIRECTION INPUT ;
    USE SIGNAL ;
    ANTENNAGATEAREA 0.213000 ;
    PORT
      LAYER met3 ;
        RECT 0.000 289.040 4.000 289.640 ;
    END
  END w20[4]
  PIN w20[5]
    DIRECTION INPUT ;
    USE SIGNAL ;
    ANTENNAGATEAREA 0.196500 ;
    PORT
      LAYER met3 ;
        RECT 0.000 295.840 4.000 296.440 ;
    END
  END w20[5]
  PIN w20[6]
    DIRECTION INPUT ;
    USE SIGNAL ;
    ANTENNAGATEAREA 0.213000 ;
    PORT
      LAYER met3 ;
        RECT 0.000 299.240 4.000 299.840 ;
    END
  END w20[6]
  PIN w20[7]
    DIRECTION INPUT ;
    USE SIGNAL ;
    ANTENNAGATEAREA 0.159000 ;
    PORT
      LAYER met3 ;
        RECT 0.000 282.240 4.000 282.840 ;
    END
  END w20[7]
  PIN w21[0]
    DIRECTION INPUT ;
    USE SIGNAL ;
    ANTENNAGATEAREA 0.213000 ;
    PORT
      LAYER met3 ;
        RECT 381.625 142.840 385.625 143.440 ;
    END
  END w21[0]
  PIN w21[1]
    DIRECTION INPUT ;
    USE SIGNAL ;
    ANTENNAGATEAREA 0.213000 ;
    PORT
      LAYER met3 ;
        RECT 381.625 105.440 385.625 106.040 ;
    END
  END w21[1]
  PIN w21[2]
    DIRECTION INPUT ;
    USE SIGNAL ;
    ANTENNAGATEAREA 0.126000 ;
    PORT
      LAYER met3 ;
        RECT 381.625 95.240 385.625 95.840 ;
    END
  END w21[2]
  PIN w21[3]
    DIRECTION INPUT ;
    USE SIGNAL ;
    ANTENNAGATEAREA 0.196500 ;
    PORT
      LAYER met3 ;
        RECT 381.625 98.640 385.625 99.240 ;
    END
  END w21[3]
  PIN w21[4]
    DIRECTION INPUT ;
    USE SIGNAL ;
    ANTENNAGATEAREA 0.213000 ;
    PORT
      LAYER met3 ;
        RECT 381.625 81.640 385.625 82.240 ;
    END
  END w21[4]
  PIN w21[5]
    DIRECTION INPUT ;
    USE SIGNAL ;
    ANTENNAGATEAREA 0.196500 ;
    PORT
      LAYER met3 ;
        RECT 381.625 71.440 385.625 72.040 ;
    END
  END w21[5]
  PIN w21[6]
    DIRECTION INPUT ;
    USE SIGNAL ;
    ANTENNAGATEAREA 0.196500 ;
    PORT
      LAYER met3 ;
        RECT 381.625 74.840 385.625 75.440 ;
    END
  END w21[6]
  PIN w21[7]
    DIRECTION INPUT ;
    USE SIGNAL ;
    ANTENNAGATEAREA 0.196500 ;
    PORT
      LAYER met2 ;
        RECT 257.690 0.000 257.970 4.000 ;
    END
  END w21[7]
  PIN w22[0]
    DIRECTION INPUT ;
    USE SIGNAL ;
    ANTENNAGATEAREA 0.196500 ;
    PORT
      LAYER met3 ;
        RECT 0.000 166.640 4.000 167.240 ;
    END
  END w22[0]
  PIN w22[1]
    DIRECTION INPUT ;
    USE SIGNAL ;
    ANTENNAGATEAREA 0.196500 ;
    PORT
      LAYER met3 ;
        RECT 0.000 136.040 4.000 136.640 ;
    END
  END w22[1]
  PIN w22[2]
    DIRECTION INPUT ;
    USE SIGNAL ;
    ANTENNAGATEAREA 0.196500 ;
    PORT
      LAYER met3 ;
        RECT 0.000 163.240 4.000 163.840 ;
    END
  END w22[2]
  PIN w22[3]
    DIRECTION INPUT ;
    USE SIGNAL ;
    ANTENNAGATEAREA 0.196500 ;
    PORT
      LAYER met3 ;
        RECT 0.000 156.440 4.000 157.040 ;
    END
  END w22[3]
  PIN w22[4]
    DIRECTION INPUT ;
    USE SIGNAL ;
    ANTENNAGATEAREA 0.213000 ;
    PORT
      LAYER met2 ;
        RECT 116.010 0.000 116.290 4.000 ;
    END
  END w22[4]
  PIN w22[5]
    DIRECTION INPUT ;
    USE SIGNAL ;
    ANTENNAGATEAREA 0.196500 ;
    PORT
      LAYER met2 ;
        RECT 122.450 0.000 122.730 4.000 ;
    END
  END w22[5]
  PIN w22[6]
    DIRECTION INPUT ;
    USE SIGNAL ;
    ANTENNAGATEAREA 0.196500 ;
    PORT
      LAYER met2 ;
        RECT 125.670 0.000 125.950 4.000 ;
    END
  END w22[6]
  PIN w22[7]
    DIRECTION INPUT ;
    USE SIGNAL ;
    ANTENNAGATEAREA 0.213000 ;
    PORT
      LAYER met3 ;
        RECT 0.000 115.640 4.000 116.240 ;
    END
  END w22[7]
  PIN w23[0]
    DIRECTION INPUT ;
    USE SIGNAL ;
    ANTENNAGATEAREA 0.213000 ;
    PORT
      LAYER met3 ;
        RECT 381.625 261.840 385.625 262.440 ;
    END
  END w23[0]
  PIN w23[1]
    DIRECTION INPUT ;
    USE SIGNAL ;
    ANTENNAGATEAREA 0.196500 ;
    PORT
      LAYER met3 ;
        RECT 381.625 275.440 385.625 276.040 ;
    END
  END w23[1]
  PIN w23[2]
    DIRECTION INPUT ;
    USE SIGNAL ;
    ANTENNAGATEAREA 0.196500 ;
    PORT
      LAYER met3 ;
        RECT 381.625 278.840 385.625 279.440 ;
    END
  END w23[2]
  PIN w23[3]
    DIRECTION INPUT ;
    USE SIGNAL ;
    ANTENNAGATEAREA 0.196500 ;
    PORT
      LAYER met3 ;
        RECT 381.625 285.640 385.625 286.240 ;
    END
  END w23[3]
  PIN w23[4]
    DIRECTION INPUT ;
    USE SIGNAL ;
    ANTENNAGATEAREA 0.213000 ;
    PORT
      LAYER met2 ;
        RECT 302.770 392.345 303.050 396.345 ;
    END
  END w23[4]
  PIN w23[5]
    DIRECTION INPUT ;
    USE SIGNAL ;
    ANTENNAGATEAREA 0.196500 ;
    PORT
      LAYER met2 ;
        RECT 299.550 392.345 299.830 396.345 ;
    END
  END w23[5]
  PIN w23[6]
    DIRECTION INPUT ;
    USE SIGNAL ;
    ANTENNAGATEAREA 0.213000 ;
    PORT
      LAYER met2 ;
        RECT 289.890 392.345 290.170 396.345 ;
    END
  END w23[6]
  PIN w23[7]
    DIRECTION INPUT ;
    USE SIGNAL ;
    ANTENNAGATEAREA 0.213000 ;
    PORT
      LAYER met2 ;
        RECT 260.910 392.345 261.190 396.345 ;
    END
  END w23[7]
  PIN w30[0]
    DIRECTION INPUT ;
    USE SIGNAL ;
    ANTENNAGATEAREA 0.196500 ;
    PORT
      LAYER met3 ;
        RECT 0.000 231.240 4.000 231.840 ;
    END
  END w30[0]
  PIN w30[1]
    DIRECTION INPUT ;
    USE SIGNAL ;
    ANTENNAGATEAREA 0.196500 ;
    PORT
      LAYER met3 ;
        RECT 0.000 238.040 4.000 238.640 ;
    END
  END w30[1]
  PIN w30[2]
    DIRECTION INPUT ;
    USE SIGNAL ;
    ANTENNAGATEAREA 0.126000 ;
    PORT
      LAYER met3 ;
        RECT 0.000 234.640 4.000 235.240 ;
    END
  END w30[2]
  PIN w30[3]
    DIRECTION INPUT ;
    USE SIGNAL ;
    ANTENNAGATEAREA 0.196500 ;
    PORT
      LAYER met3 ;
        RECT 0.000 241.440 4.000 242.040 ;
    END
  END w30[3]
  PIN w30[4]
    DIRECTION INPUT ;
    USE SIGNAL ;
    ANTENNAGATEAREA 0.196500 ;
    PORT
      LAYER met3 ;
        RECT 0.000 248.240 4.000 248.840 ;
    END
  END w30[4]
  PIN w30[5]
    DIRECTION INPUT ;
    USE SIGNAL ;
    ANTENNAGATEAREA 0.196500 ;
    PORT
      LAYER met3 ;
        RECT 0.000 251.640 4.000 252.240 ;
    END
  END w30[5]
  PIN w30[6]
    DIRECTION INPUT ;
    USE SIGNAL ;
    ANTENNAGATEAREA 0.213000 ;
    PORT
      LAYER met3 ;
        RECT 0.000 255.040 4.000 255.640 ;
    END
  END w30[6]
  PIN w30[7]
    DIRECTION INPUT ;
    USE SIGNAL ;
    ANTENNAGATEAREA 0.159000 ;
    PORT
      LAYER met3 ;
        RECT 0.000 258.440 4.000 259.040 ;
    END
  END w30[7]
  PIN w31[0]
    DIRECTION INPUT ;
    USE SIGNAL ;
    ANTENNAGATEAREA 0.196500 ;
    PORT
      LAYER met2 ;
        RECT 238.370 0.000 238.650 4.000 ;
    END
  END w31[0]
  PIN w31[1]
    DIRECTION INPUT ;
    USE SIGNAL ;
    ANTENNAGATEAREA 0.196500 ;
    PORT
      LAYER met2 ;
        RECT 254.470 0.000 254.750 4.000 ;
    END
  END w31[1]
  PIN w31[2]
    DIRECTION INPUT ;
    USE SIGNAL ;
    ANTENNAGATEAREA 0.126000 ;
    PORT
      LAYER met2 ;
        RECT 241.590 0.000 241.870 4.000 ;
    END
  END w31[2]
  PIN w31[3]
    DIRECTION INPUT ;
    USE SIGNAL ;
    ANTENNAGATEAREA 0.213000 ;
    PORT
      LAYER met2 ;
        RECT 235.150 0.000 235.430 4.000 ;
    END
  END w31[3]
  PIN w31[4]
    DIRECTION INPUT ;
    USE SIGNAL ;
    ANTENNAGATEAREA 0.196500 ;
    PORT
      LAYER met2 ;
        RECT 244.810 0.000 245.090 4.000 ;
    END
  END w31[4]
  PIN w31[5]
    DIRECTION INPUT ;
    USE SIGNAL ;
    ANTENNAGATEAREA 0.196500 ;
    PORT
      LAYER met2 ;
        RECT 248.030 0.000 248.310 4.000 ;
    END
  END w31[5]
  PIN w31[6]
    DIRECTION INPUT ;
    USE SIGNAL ;
    ANTENNAGATEAREA 0.196500 ;
    PORT
      LAYER met2 ;
        RECT 251.250 0.000 251.530 4.000 ;
    END
  END w31[6]
  PIN w31[7]
    DIRECTION INPUT ;
    USE SIGNAL ;
    ANTENNAGATEAREA 0.159000 ;
    PORT
      LAYER met2 ;
        RECT 231.930 0.000 232.210 4.000 ;
    END
  END w31[7]
  PIN w32[0]
    DIRECTION INPUT ;
    USE SIGNAL ;
    ANTENNAGATEAREA 0.196500 ;
    PORT
      LAYER met3 ;
        RECT 0.000 102.040 4.000 102.640 ;
    END
  END w32[0]
  PIN w32[1]
    DIRECTION INPUT ;
    USE SIGNAL ;
    ANTENNAGATEAREA 0.196500 ;
    PORT
      LAYER met3 ;
        RECT 0.000 149.640 4.000 150.240 ;
    END
  END w32[1]
  PIN w32[2]
    DIRECTION INPUT ;
    USE SIGNAL ;
    ANTENNAGATEAREA 0.196500 ;
    PORT
      LAYER met3 ;
        RECT 0.000 146.240 4.000 146.840 ;
    END
  END w32[2]
  PIN w32[3]
    DIRECTION INPUT ;
    USE SIGNAL ;
    ANTENNAGATEAREA 0.126000 ;
    PORT
      LAYER met3 ;
        RECT 0.000 108.840 4.000 109.440 ;
    END
  END w32[3]
  PIN w32[4]
    DIRECTION INPUT ;
    USE SIGNAL ;
    ANTENNAGATEAREA 0.196500 ;
    PORT
      LAYER met3 ;
        RECT 0.000 119.040 4.000 119.640 ;
    END
  END w32[4]
  PIN w32[5]
    DIRECTION INPUT ;
    USE SIGNAL ;
    ANTENNAGATEAREA 0.196500 ;
    PORT
      LAYER met3 ;
        RECT 0.000 125.840 4.000 126.440 ;
    END
  END w32[5]
  PIN w32[6]
    DIRECTION INPUT ;
    USE SIGNAL ;
    ANTENNAGATEAREA 0.196500 ;
    PORT
      LAYER met3 ;
        RECT 0.000 129.240 4.000 129.840 ;
    END
  END w32[6]
  PIN w32[7]
    DIRECTION INPUT ;
    USE SIGNAL ;
    ANTENNAGATEAREA 0.159000 ;
    PORT
      LAYER met3 ;
        RECT 0.000 71.440 4.000 72.040 ;
    END
  END w32[7]
  PIN w33[0]
    DIRECTION INPUT ;
    USE SIGNAL ;
    ANTENNAGATEAREA 0.196500 ;
    PORT
      LAYER met3 ;
        RECT 381.625 231.240 385.625 231.840 ;
    END
  END w33[0]
  PIN w33[1]
    DIRECTION INPUT ;
    USE SIGNAL ;
    ANTENNAGATEAREA 0.196500 ;
    PORT
      LAYER met3 ;
        RECT 381.625 238.040 385.625 238.640 ;
    END
  END w33[1]
  PIN w33[2]
    DIRECTION INPUT ;
    USE SIGNAL ;
    ANTENNAGATEAREA 0.196500 ;
    PORT
      LAYER met3 ;
        RECT 381.625 234.640 385.625 235.240 ;
    END
  END w33[2]
  PIN w33[3]
    DIRECTION INPUT ;
    USE SIGNAL ;
    ANTENNAGATEAREA 0.126000 ;
    PORT
      LAYER met3 ;
        RECT 381.625 248.240 385.625 248.840 ;
    END
  END w33[3]
  PIN w33[4]
    DIRECTION INPUT ;
    USE SIGNAL ;
    ANTENNAGATEAREA 0.196500 ;
    PORT
      LAYER met3 ;
        RECT 381.625 268.640 385.625 269.240 ;
    END
  END w33[4]
  PIN w33[5]
    DIRECTION INPUT ;
    USE SIGNAL ;
    ANTENNAGATEAREA 0.196500 ;
    PORT
      LAYER met3 ;
        RECT 381.625 255.040 385.625 255.640 ;
    END
  END w33[5]
  PIN w33[6]
    DIRECTION INPUT ;
    USE SIGNAL ;
    ANTENNAGATEAREA 0.213000 ;
    PORT
      LAYER met2 ;
        RECT 273.790 392.345 274.070 396.345 ;
    END
  END w33[6]
  PIN w33[7]
    DIRECTION INPUT ;
    USE SIGNAL ;
    ANTENNAGATEAREA 0.213000 ;
    PORT
      LAYER met3 ;
        RECT 381.625 258.440 385.625 259.040 ;
    END
  END w33[7]
  OBS
      LAYER nwell ;
        RECT 5.330 10.795 380.150 383.710 ;
      LAYER li1 ;
        RECT 5.520 10.795 379.960 383.605 ;
      LAYER met1 ;
        RECT 4.210 10.640 380.260 383.760 ;
      LAYER met2 ;
        RECT 4.230 392.065 96.410 392.770 ;
        RECT 97.250 392.065 99.630 392.770 ;
        RECT 100.470 392.065 118.950 392.770 ;
        RECT 119.790 392.065 128.610 392.770 ;
        RECT 129.450 392.065 135.050 392.770 ;
        RECT 135.890 392.065 138.270 392.770 ;
        RECT 139.110 392.065 141.490 392.770 ;
        RECT 142.330 392.065 144.710 392.770 ;
        RECT 145.550 392.065 147.930 392.770 ;
        RECT 148.770 392.065 151.150 392.770 ;
        RECT 151.990 392.065 154.370 392.770 ;
        RECT 155.210 392.065 157.590 392.770 ;
        RECT 158.430 392.065 160.810 392.770 ;
        RECT 161.650 392.065 164.030 392.770 ;
        RECT 164.870 392.065 167.250 392.770 ;
        RECT 168.090 392.065 170.470 392.770 ;
        RECT 171.310 392.065 173.690 392.770 ;
        RECT 174.530 392.065 180.130 392.770 ;
        RECT 180.970 392.065 183.350 392.770 ;
        RECT 184.190 392.065 186.570 392.770 ;
        RECT 187.410 392.065 189.790 392.770 ;
        RECT 190.630 392.065 193.010 392.770 ;
        RECT 193.850 392.065 196.230 392.770 ;
        RECT 197.070 392.065 199.450 392.770 ;
        RECT 200.290 392.065 202.670 392.770 ;
        RECT 203.510 392.065 205.890 392.770 ;
        RECT 206.730 392.065 209.110 392.770 ;
        RECT 209.950 392.065 260.630 392.770 ;
        RECT 261.470 392.065 263.850 392.770 ;
        RECT 264.690 392.065 267.070 392.770 ;
        RECT 267.910 392.065 273.510 392.770 ;
        RECT 274.350 392.065 276.730 392.770 ;
        RECT 277.570 392.065 283.170 392.770 ;
        RECT 284.010 392.065 289.610 392.770 ;
        RECT 290.450 392.065 299.270 392.770 ;
        RECT 300.110 392.065 302.490 392.770 ;
        RECT 303.330 392.065 305.710 392.770 ;
        RECT 306.550 392.065 308.930 392.770 ;
        RECT 309.770 392.065 312.150 392.770 ;
        RECT 312.990 392.065 315.370 392.770 ;
        RECT 316.210 392.065 318.590 392.770 ;
        RECT 319.430 392.065 321.810 392.770 ;
        RECT 322.650 392.065 325.030 392.770 ;
        RECT 325.870 392.065 328.250 392.770 ;
        RECT 329.090 392.065 331.470 392.770 ;
        RECT 332.310 392.065 334.690 392.770 ;
        RECT 335.530 392.065 337.910 392.770 ;
        RECT 338.750 392.065 379.400 392.770 ;
        RECT 4.230 4.280 379.400 392.065 ;
        RECT 4.230 4.000 19.130 4.280 ;
        RECT 19.970 4.000 115.730 4.280 ;
        RECT 116.570 4.000 122.170 4.280 ;
        RECT 123.010 4.000 125.390 4.280 ;
        RECT 126.230 4.000 138.270 4.280 ;
        RECT 139.110 4.000 141.490 4.280 ;
        RECT 142.330 4.000 144.710 4.280 ;
        RECT 145.550 4.000 154.370 4.280 ;
        RECT 155.210 4.000 170.470 4.280 ;
        RECT 171.310 4.000 173.690 4.280 ;
        RECT 174.530 4.000 176.910 4.280 ;
        RECT 177.750 4.000 180.130 4.280 ;
        RECT 180.970 4.000 183.350 4.280 ;
        RECT 184.190 4.000 186.570 4.280 ;
        RECT 187.410 4.000 189.790 4.280 ;
        RECT 190.630 4.000 193.010 4.280 ;
        RECT 193.850 4.000 196.230 4.280 ;
        RECT 197.070 4.000 199.450 4.280 ;
        RECT 200.290 4.000 202.670 4.280 ;
        RECT 203.510 4.000 205.890 4.280 ;
        RECT 206.730 4.000 209.110 4.280 ;
        RECT 209.950 4.000 212.330 4.280 ;
        RECT 213.170 4.000 215.550 4.280 ;
        RECT 216.390 4.000 218.770 4.280 ;
        RECT 219.610 4.000 221.990 4.280 ;
        RECT 222.830 4.000 225.210 4.280 ;
        RECT 226.050 4.000 228.430 4.280 ;
        RECT 229.270 4.000 231.650 4.280 ;
        RECT 232.490 4.000 234.870 4.280 ;
        RECT 235.710 4.000 238.090 4.280 ;
        RECT 238.930 4.000 241.310 4.280 ;
        RECT 242.150 4.000 244.530 4.280 ;
        RECT 245.370 4.000 247.750 4.280 ;
        RECT 248.590 4.000 250.970 4.280 ;
        RECT 251.810 4.000 254.190 4.280 ;
        RECT 255.030 4.000 257.410 4.280 ;
        RECT 258.250 4.000 260.630 4.280 ;
        RECT 261.470 4.000 379.400 4.280 ;
      LAYER met3 ;
        RECT 3.750 351.240 381.625 383.685 ;
        RECT 3.750 349.840 381.225 351.240 ;
        RECT 3.750 347.840 381.625 349.840 ;
        RECT 3.750 346.440 381.225 347.840 ;
        RECT 3.750 344.440 381.625 346.440 ;
        RECT 3.750 343.040 381.225 344.440 ;
        RECT 3.750 341.040 381.625 343.040 ;
        RECT 3.750 339.640 381.225 341.040 ;
        RECT 3.750 337.640 381.625 339.640 ;
        RECT 4.400 336.240 381.625 337.640 ;
        RECT 3.750 334.240 381.625 336.240 ;
        RECT 3.750 332.840 381.225 334.240 ;
        RECT 3.750 300.240 381.625 332.840 ;
        RECT 4.400 298.840 381.225 300.240 ;
        RECT 3.750 296.840 381.625 298.840 ;
        RECT 4.400 295.440 381.225 296.840 ;
        RECT 3.750 293.440 381.625 295.440 ;
        RECT 4.400 292.040 381.225 293.440 ;
        RECT 3.750 290.040 381.625 292.040 ;
        RECT 4.400 288.640 381.225 290.040 ;
        RECT 3.750 286.640 381.625 288.640 ;
        RECT 4.400 285.240 381.225 286.640 ;
        RECT 3.750 283.240 381.625 285.240 ;
        RECT 4.400 281.840 381.225 283.240 ;
        RECT 3.750 279.840 381.625 281.840 ;
        RECT 4.400 278.440 381.225 279.840 ;
        RECT 3.750 276.440 381.625 278.440 ;
        RECT 4.400 275.040 381.225 276.440 ;
        RECT 3.750 273.040 381.625 275.040 ;
        RECT 4.400 271.640 381.225 273.040 ;
        RECT 3.750 269.640 381.625 271.640 ;
        RECT 3.750 268.240 381.225 269.640 ;
        RECT 3.750 266.240 381.625 268.240 ;
        RECT 3.750 264.840 381.225 266.240 ;
        RECT 3.750 262.840 381.625 264.840 ;
        RECT 4.400 261.440 381.225 262.840 ;
        RECT 3.750 259.440 381.625 261.440 ;
        RECT 4.400 258.040 381.225 259.440 ;
        RECT 3.750 256.040 381.625 258.040 ;
        RECT 4.400 254.640 381.225 256.040 ;
        RECT 3.750 252.640 381.625 254.640 ;
        RECT 4.400 251.240 381.225 252.640 ;
        RECT 3.750 249.240 381.625 251.240 ;
        RECT 4.400 247.840 381.225 249.240 ;
        RECT 3.750 245.840 381.625 247.840 ;
        RECT 4.400 244.440 381.225 245.840 ;
        RECT 3.750 242.440 381.625 244.440 ;
        RECT 4.400 241.040 381.225 242.440 ;
        RECT 3.750 239.040 381.625 241.040 ;
        RECT 4.400 237.640 381.225 239.040 ;
        RECT 3.750 235.640 381.625 237.640 ;
        RECT 4.400 234.240 381.225 235.640 ;
        RECT 3.750 232.240 381.625 234.240 ;
        RECT 4.400 230.840 381.225 232.240 ;
        RECT 3.750 228.840 381.625 230.840 ;
        RECT 4.400 227.440 381.225 228.840 ;
        RECT 3.750 225.440 381.625 227.440 ;
        RECT 4.400 224.040 381.225 225.440 ;
        RECT 3.750 222.040 381.625 224.040 ;
        RECT 4.400 220.640 381.225 222.040 ;
        RECT 3.750 218.640 381.625 220.640 ;
        RECT 4.400 217.240 381.225 218.640 ;
        RECT 3.750 215.240 381.625 217.240 ;
        RECT 4.400 213.840 381.225 215.240 ;
        RECT 3.750 211.840 381.625 213.840 ;
        RECT 4.400 210.440 381.225 211.840 ;
        RECT 3.750 208.440 381.625 210.440 ;
        RECT 4.400 207.040 381.225 208.440 ;
        RECT 3.750 205.040 381.625 207.040 ;
        RECT 4.400 203.640 381.225 205.040 ;
        RECT 3.750 201.640 381.625 203.640 ;
        RECT 4.400 200.240 381.225 201.640 ;
        RECT 3.750 198.240 381.625 200.240 ;
        RECT 4.400 196.840 381.225 198.240 ;
        RECT 3.750 194.840 381.625 196.840 ;
        RECT 4.400 193.440 381.225 194.840 ;
        RECT 3.750 191.440 381.625 193.440 ;
        RECT 4.400 190.040 381.225 191.440 ;
        RECT 3.750 188.040 381.625 190.040 ;
        RECT 4.400 186.640 381.225 188.040 ;
        RECT 3.750 184.640 381.625 186.640 ;
        RECT 4.400 183.240 381.225 184.640 ;
        RECT 3.750 181.240 381.625 183.240 ;
        RECT 4.400 179.840 381.225 181.240 ;
        RECT 3.750 177.840 381.625 179.840 ;
        RECT 4.400 176.440 381.225 177.840 ;
        RECT 3.750 174.440 381.625 176.440 ;
        RECT 4.400 173.040 381.225 174.440 ;
        RECT 3.750 171.040 381.625 173.040 ;
        RECT 4.400 169.640 381.225 171.040 ;
        RECT 3.750 167.640 381.625 169.640 ;
        RECT 4.400 166.240 381.225 167.640 ;
        RECT 3.750 164.240 381.625 166.240 ;
        RECT 4.400 162.840 381.625 164.240 ;
        RECT 3.750 160.840 381.625 162.840 ;
        RECT 4.400 159.440 381.225 160.840 ;
        RECT 3.750 157.440 381.625 159.440 ;
        RECT 4.400 156.040 381.625 157.440 ;
        RECT 3.750 154.040 381.625 156.040 ;
        RECT 4.400 152.640 381.625 154.040 ;
        RECT 3.750 150.640 381.625 152.640 ;
        RECT 4.400 149.240 381.225 150.640 ;
        RECT 3.750 147.240 381.625 149.240 ;
        RECT 4.400 145.840 381.625 147.240 ;
        RECT 3.750 143.840 381.625 145.840 ;
        RECT 4.400 142.440 381.225 143.840 ;
        RECT 3.750 140.440 381.625 142.440 ;
        RECT 4.400 139.040 381.225 140.440 ;
        RECT 3.750 137.040 381.625 139.040 ;
        RECT 4.400 135.640 381.225 137.040 ;
        RECT 3.750 133.640 381.625 135.640 ;
        RECT 4.400 132.240 381.225 133.640 ;
        RECT 3.750 130.240 381.625 132.240 ;
        RECT 4.400 128.840 381.225 130.240 ;
        RECT 3.750 126.840 381.625 128.840 ;
        RECT 4.400 125.440 381.225 126.840 ;
        RECT 3.750 123.440 381.625 125.440 ;
        RECT 4.400 122.040 381.225 123.440 ;
        RECT 3.750 120.040 381.625 122.040 ;
        RECT 4.400 118.640 381.225 120.040 ;
        RECT 3.750 116.640 381.625 118.640 ;
        RECT 4.400 115.240 381.625 116.640 ;
        RECT 3.750 113.240 381.625 115.240 ;
        RECT 4.400 111.840 381.225 113.240 ;
        RECT 3.750 109.840 381.625 111.840 ;
        RECT 4.400 108.440 381.225 109.840 ;
        RECT 3.750 106.440 381.625 108.440 ;
        RECT 4.400 105.040 381.225 106.440 ;
        RECT 3.750 103.040 381.625 105.040 ;
        RECT 4.400 101.640 381.225 103.040 ;
        RECT 3.750 99.640 381.625 101.640 ;
        RECT 4.400 98.240 381.225 99.640 ;
        RECT 3.750 96.240 381.625 98.240 ;
        RECT 4.400 94.840 381.225 96.240 ;
        RECT 3.750 92.840 381.625 94.840 ;
        RECT 4.400 91.440 381.225 92.840 ;
        RECT 3.750 89.440 381.625 91.440 ;
        RECT 4.400 88.040 381.225 89.440 ;
        RECT 3.750 86.040 381.625 88.040 ;
        RECT 4.400 84.640 381.225 86.040 ;
        RECT 3.750 82.640 381.625 84.640 ;
        RECT 4.400 81.240 381.225 82.640 ;
        RECT 3.750 79.240 381.625 81.240 ;
        RECT 4.400 77.840 381.225 79.240 ;
        RECT 3.750 75.840 381.625 77.840 ;
        RECT 4.400 74.440 381.225 75.840 ;
        RECT 3.750 72.440 381.625 74.440 ;
        RECT 4.400 71.040 381.225 72.440 ;
        RECT 3.750 69.040 381.625 71.040 ;
        RECT 4.400 67.640 381.625 69.040 ;
        RECT 3.750 65.640 381.625 67.640 ;
        RECT 4.400 64.240 381.625 65.640 ;
        RECT 3.750 62.240 381.625 64.240 ;
        RECT 4.400 60.840 381.225 62.240 ;
        RECT 3.750 52.040 381.625 60.840 ;
        RECT 3.750 50.640 381.225 52.040 ;
        RECT 3.750 48.640 381.625 50.640 ;
        RECT 3.750 47.240 381.225 48.640 ;
        RECT 3.750 45.240 381.625 47.240 ;
        RECT 3.750 43.840 381.225 45.240 ;
        RECT 3.750 10.715 381.625 43.840 ;
      LAYER met4 ;
        RECT 3.975 13.095 20.640 359.545 ;
        RECT 23.040 13.095 23.940 359.545 ;
        RECT 26.340 13.095 174.240 359.545 ;
        RECT 176.640 13.095 177.540 359.545 ;
        RECT 179.940 13.095 327.840 359.545 ;
        RECT 330.240 13.095 331.140 359.545 ;
        RECT 333.540 13.095 366.785 359.545 ;
      LAYER met5 ;
        RECT 32.780 283.100 200.900 284.700 ;
  END
END crossbar_mac
END LIBRARY

